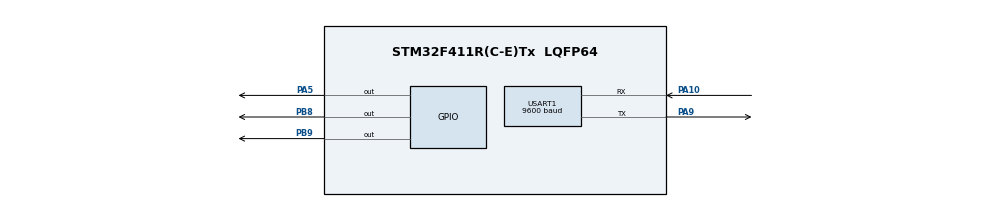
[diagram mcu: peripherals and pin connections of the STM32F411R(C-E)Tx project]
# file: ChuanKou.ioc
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Mcu.Family=STM32F4
Mcu.Name=STM32F411R(C-E)Tx
Mcu.Package=LQFP64
NVIC.PriorityGroup=NVIC_PRIORITYGROUP_4
NVIC.USART1_IRQn=true\:0\:0\:false\:false\:true\:true\:true\:true
PA10.Mode=Asynchronous
PA10.Signal=USART1_RX
PA13.Mode=Serial_Wire
PA13.Signal=SYS_JTMS-SWDIO
PA14.Mode=Serial_Wire
PA14.Signal=SYS_JTCK-SWCLK
PA5.Signal=GPIO_Output
PA9.Mode=Asynchronous
PA9.Signal=USART1_TX
PB8.Signal=GPIO_Output
PB9.Signal=GPIO_Output
PC14-OSC32_IN.Mode=LSE-External-Oscillator
PC14-OSC32_IN.Signal=RCC_OSC32_IN
PC15-OSC32_OUT.Mode=LSE-External-Oscillator
PC15-OSC32_OUT.Signal=RCC_OSC32_OUT
PH0\ -\ OSC_IN.Mode=HSE-External-Oscillator
PH0\ -\ OSC_IN.Signal=RCC_OSC_IN
PH1\ -\ OSC_OUT.Mode=HSE-External-Oscillator
PH1\ -\ OSC_OUT.Signal=RCC_OSC_OUT
ProjectManager.HeapSize=0x200
ProjectManager.StackSize=0x400
ProjectManager.TargetToolchain=MDK-ARM V5
RCC.48MHZClocksFreq_Value=18000000
RCC.AHBCLKDivider=RCC_SYSCLK_DIV2
RCC.AHBFreq_Value=6000000
RCC.APB1CLKDivider=RCC_HCLK_DIV2
RCC.APB1Freq_Value=3000000
RCC.APB1TimFreq_Value=6000000
RCC.APB2Freq_Value=6000000
RCC.APB2TimFreq_Value=6000000
RCC.CortexFreq_Value=6000000
RCC.HCLKFreq_Value=6000000
RCC.HSE_VALUE=8000000
RCC.HSI_VALUE=16000000
RCC.PLLM=8
RCC.PLLN=72
RCC.PLLP=RCC_PLLP_DIV6
RCC.PLLSourceVirtual=RCC_PLLSOURCE_HSE
RCC.SYSCLKFreq_VALUE=12000000
RCC.SYSCLKSource=RCC_SYSCLKSOURCE_PLLCLK
RCC.VCOOutputFreq_Value=72000000
USART1.BaudRate=9600
USART1.VirtualMode=VM_ASYNC
board=custom

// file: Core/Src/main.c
/* USER CODE BEGIN Header */
/**
  ******************************************************************************
  * @file           : main.c
  * @brief          : Main program body
  ******************************************************************************
  * @attention
  *
  * Copyright (c) 2023 STMicroelectronics.
  * All rights reserved.
  *
  * This software is licensed under terms that can be found in the LICENSE file
  * in the root directory of this software component.
  * If no LICENSE file comes with this software, it is provided AS-IS.
  *
  ******************************************************************************
  */
/* USER CODE END Header */
#include "main.h"
#include "usart.h"
#include "gpio.h"

void SystemClock_Config(void);

int main(void)
{

  /* MCU Configuration--------------------------------------------------------*/

  /* Reset of all peripherals, Initializes the Flash interface and the Systick. */
  HAL_Init();

  /* Configure the system clock */
  SystemClock_Config();

  /* Initialize all configured peripherals */
  MX_GPIO_Init();
  MX_USART1_UART_Init();

  /* Infinite loop */
  while (1)
  {

  }
}

void SystemClock_Config(void)
{
  RCC_OscInitTypeDef RCC_OscInitStruct = {0};
  RCC_ClkInitTypeDef RCC_ClkInitStruct = {0};

  /** Configure the main internal regulator output voltage
  */
  __HAL_RCC_PWR_CLK_ENABLE();
  __HAL_PWR_VOLTAGESCALING_CONFIG(PWR_REGULATOR_VOLTAGE_SCALE1);

  /** Initializes the RCC Oscillators according to the specified parameters
  * in the RCC_OscInitTypeDef structure.
  */
  RCC_OscInitStruct.OscillatorType = RCC_OSCILLATORTYPE_HSE;
  RCC_OscInitStruct.HSEState = RCC_HSE_ON;
  RCC_OscInitStruct.PLL.PLLState = RCC_PLL_ON;
  RCC_OscInitStruct.PLL.PLLSource = RCC_PLLSOURCE_HSE;
  RCC_OscInitStruct.PLL.PLLM = 4;
  RCC_OscInitStruct.PLL.PLLN = 100;
  RCC_OscInitStruct.PLL.PLLP = RCC_PLLP_DIV2;
  RCC_OscInitStruct.PLL.PLLQ = 4;
  if (HAL_RCC_OscConfig(&RCC_OscInitStruct) != HAL_OK)
  {
    Error_Handler();
  }

  /** Initializes the CPU, AHB and APB buses clocks
  */
  RCC_ClkInitStruct.ClockType = RCC_CLOCKTYPE_HCLK|RCC_CLOCKTYPE_SYSCLK
                              |RCC_CLOCKTYPE_PCLK1|RCC_CLOCKTYPE_PCLK2;
  RCC_ClkInitStruct.SYSCLKSource = RCC_SYSCLKSOURCE_PLLCLK;
  RCC_ClkInitStruct.AHBCLKDivider = RCC_SYSCLK_DIV1;
  RCC_ClkInitStruct.APB1CLKDivider = RCC_HCLK_DIV2;
  RCC_ClkInitStruct.APB2CLKDivider = RCC_HCLK_DIV1;

  if (HAL_RCC_ClockConfig(&RCC_ClkInitStruct, FLASH_LATENCY_3) != HAL_OK)
  {
    Error_Handler();
  }
}

void Error_Handler(void)
{
  __disable_irq();
  while (1)
  {
  }
}
